VERSION 5.7 ;
BUSBITCHARS "[]" ;
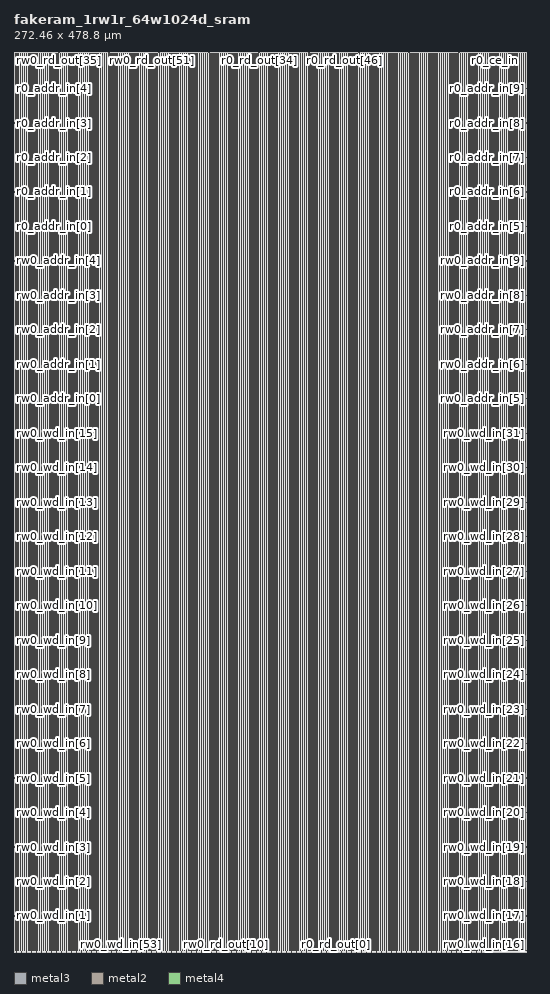
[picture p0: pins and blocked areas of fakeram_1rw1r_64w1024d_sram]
MACRO fakeram_1rw1r_64w1024d_sram
  FOREIGN fakeram_1rw1r_64w1024d_sram 0 0 ;
  SYMMETRY X Y R90 ;
  SIZE 272.460 BY 478.800 ;
  CLASS BLOCK ;
  PIN rw0_wd_in[0]
    DIRECTION INPUT ;
    USE SIGNAL ;
    SHAPE ABUTMENT ;
    PORT
      LAYER metal3 ;
      RECT 0.000 0.805 0.210 0.875 ;
    END
  END rw0_wd_in[0]
  PIN rw0_wd_in[1]
    DIRECTION INPUT ;
    USE SIGNAL ;
    SHAPE ABUTMENT ;
    PORT
      LAYER metal3 ;
      RECT 0.000 19.145 0.210 19.215 ;
    END
  END rw0_wd_in[1]
  PIN rw0_wd_in[2]
    DIRECTION INPUT ;
    USE SIGNAL ;
    SHAPE ABUTMENT ;
    PORT
      LAYER metal3 ;
      RECT 0.000 37.485 0.210 37.555 ;
    END
  END rw0_wd_in[2]
  PIN rw0_wd_in[3]
    DIRECTION INPUT ;
    USE SIGNAL ;
    SHAPE ABUTMENT ;
    PORT
      LAYER metal3 ;
      RECT 0.000 55.825 0.210 55.895 ;
    END
  END rw0_wd_in[3]
  PIN rw0_wd_in[4]
    DIRECTION INPUT ;
    USE SIGNAL ;
    SHAPE ABUTMENT ;
    PORT
      LAYER metal3 ;
      RECT 0.000 74.165 0.210 74.235 ;
    END
  END rw0_wd_in[4]
  PIN rw0_wd_in[5]
    DIRECTION INPUT ;
    USE SIGNAL ;
    SHAPE ABUTMENT ;
    PORT
      LAYER metal3 ;
      RECT 0.000 92.505 0.210 92.575 ;
    END
  END rw0_wd_in[5]
  PIN rw0_wd_in[6]
    DIRECTION INPUT ;
    USE SIGNAL ;
    SHAPE ABUTMENT ;
    PORT
      LAYER metal3 ;
      RECT 0.000 110.845 0.210 110.915 ;
    END
  END rw0_wd_in[6]
  PIN rw0_wd_in[7]
    DIRECTION INPUT ;
    USE SIGNAL ;
    SHAPE ABUTMENT ;
    PORT
      LAYER metal3 ;
      RECT 0.000 129.185 0.210 129.255 ;
    END
  END rw0_wd_in[7]
  PIN rw0_wd_in[8]
    DIRECTION INPUT ;
    USE SIGNAL ;
    SHAPE ABUTMENT ;
    PORT
      LAYER metal3 ;
      RECT 0.000 147.525 0.210 147.595 ;
    END
  END rw0_wd_in[8]
  PIN rw0_wd_in[9]
    DIRECTION INPUT ;
    USE SIGNAL ;
    SHAPE ABUTMENT ;
    PORT
      LAYER metal3 ;
      RECT 0.000 165.865 0.210 165.935 ;
    END
  END rw0_wd_in[9]
  PIN rw0_wd_in[10]
    DIRECTION INPUT ;
    USE SIGNAL ;
    SHAPE ABUTMENT ;
    PORT
      LAYER metal3 ;
      RECT 0.000 184.205 0.210 184.275 ;
    END
  END rw0_wd_in[10]
  PIN rw0_wd_in[11]
    DIRECTION INPUT ;
    USE SIGNAL ;
    SHAPE ABUTMENT ;
    PORT
      LAYER metal3 ;
      RECT 0.000 202.545 0.210 202.615 ;
    END
  END rw0_wd_in[11]
  PIN rw0_wd_in[12]
    DIRECTION INPUT ;
    USE SIGNAL ;
    SHAPE ABUTMENT ;
    PORT
      LAYER metal3 ;
      RECT 0.000 220.885 0.210 220.955 ;
    END
  END rw0_wd_in[12]
  PIN rw0_wd_in[13]
    DIRECTION INPUT ;
    USE SIGNAL ;
    SHAPE ABUTMENT ;
    PORT
      LAYER metal3 ;
      RECT 0.000 239.225 0.210 239.295 ;
    END
  END rw0_wd_in[13]
  PIN rw0_wd_in[14]
    DIRECTION INPUT ;
    USE SIGNAL ;
    SHAPE ABUTMENT ;
    PORT
      LAYER metal3 ;
      RECT 0.000 257.565 0.210 257.635 ;
    END
  END rw0_wd_in[14]
  PIN rw0_wd_in[15]
    DIRECTION INPUT ;
    USE SIGNAL ;
    SHAPE ABUTMENT ;
    PORT
      LAYER metal3 ;
      RECT 0.000 275.905 0.210 275.975 ;
    END
  END rw0_wd_in[15]
  PIN rw0_wd_in[16]
    DIRECTION INPUT ;
    USE SIGNAL ;
    SHAPE ABUTMENT ;
    PORT
      LAYER metal3 ;
      RECT 272.250 0.805 272.460 0.875 ;
    END
  END rw0_wd_in[16]
  PIN rw0_wd_in[17]
    DIRECTION INPUT ;
    USE SIGNAL ;
    SHAPE ABUTMENT ;
    PORT
      LAYER metal3 ;
      RECT 272.250 19.145 272.460 19.215 ;
    END
  END rw0_wd_in[17]
  PIN rw0_wd_in[18]
    DIRECTION INPUT ;
    USE SIGNAL ;
    SHAPE ABUTMENT ;
    PORT
      LAYER metal3 ;
      RECT 272.250 37.485 272.460 37.555 ;
    END
  END rw0_wd_in[18]
  PIN rw0_wd_in[19]
    DIRECTION INPUT ;
    USE SIGNAL ;
    SHAPE ABUTMENT ;
    PORT
      LAYER metal3 ;
      RECT 272.250 55.825 272.460 55.895 ;
    END
  END rw0_wd_in[19]
  PIN rw0_wd_in[20]
    DIRECTION INPUT ;
    USE SIGNAL ;
    SHAPE ABUTMENT ;
    PORT
      LAYER metal3 ;
      RECT 272.250 74.165 272.460 74.235 ;
    END
  END rw0_wd_in[20]
  PIN rw0_wd_in[21]
    DIRECTION INPUT ;
    USE SIGNAL ;
    SHAPE ABUTMENT ;
    PORT
      LAYER metal3 ;
      RECT 272.250 92.505 272.460 92.575 ;
    END
  END rw0_wd_in[21]
  PIN rw0_wd_in[22]
    DIRECTION INPUT ;
    USE SIGNAL ;
    SHAPE ABUTMENT ;
    PORT
      LAYER metal3 ;
      RECT 272.250 110.845 272.460 110.915 ;
    END
  END rw0_wd_in[22]
  PIN rw0_wd_in[23]
    DIRECTION INPUT ;
    USE SIGNAL ;
    SHAPE ABUTMENT ;
    PORT
      LAYER metal3 ;
      RECT 272.250 129.185 272.460 129.255 ;
    END
  END rw0_wd_in[23]
  PIN rw0_wd_in[24]
    DIRECTION INPUT ;
    USE SIGNAL ;
    SHAPE ABUTMENT ;
    PORT
      LAYER metal3 ;
      RECT 272.250 147.525 272.460 147.595 ;
    END
  END rw0_wd_in[24]
  PIN rw0_wd_in[25]
    DIRECTION INPUT ;
    USE SIGNAL ;
    SHAPE ABUTMENT ;
    PORT
      LAYER metal3 ;
      RECT 272.250 165.865 272.460 165.935 ;
    END
  END rw0_wd_in[25]
  PIN rw0_wd_in[26]
    DIRECTION INPUT ;
    USE SIGNAL ;
    SHAPE ABUTMENT ;
    PORT
      LAYER metal3 ;
      RECT 272.250 184.205 272.460 184.275 ;
    END
  END rw0_wd_in[26]
  PIN rw0_wd_in[27]
    DIRECTION INPUT ;
    USE SIGNAL ;
    SHAPE ABUTMENT ;
    PORT
      LAYER metal3 ;
      RECT 272.250 202.545 272.460 202.615 ;
    END
  END rw0_wd_in[27]
  PIN rw0_wd_in[28]
    DIRECTION INPUT ;
    USE SIGNAL ;
    SHAPE ABUTMENT ;
    PORT
      LAYER metal3 ;
      RECT 272.250 220.885 272.460 220.955 ;
    END
  END rw0_wd_in[28]
  PIN rw0_wd_in[29]
    DIRECTION INPUT ;
    USE SIGNAL ;
    SHAPE ABUTMENT ;
    PORT
      LAYER metal3 ;
      RECT 272.250 239.225 272.460 239.295 ;
    END
  END rw0_wd_in[29]
  PIN rw0_wd_in[30]
    DIRECTION INPUT ;
    USE SIGNAL ;
    SHAPE ABUTMENT ;
    PORT
      LAYER metal3 ;
      RECT 272.250 257.565 272.460 257.635 ;
    END
  END rw0_wd_in[30]
  PIN rw0_wd_in[31]
    DIRECTION INPUT ;
    USE SIGNAL ;
    SHAPE ABUTMENT ;
    PORT
      LAYER metal3 ;
      RECT 272.250 275.905 272.460 275.975 ;
    END
  END rw0_wd_in[31]
  PIN rw0_wd_in[32]
    DIRECTION INPUT ;
    USE SIGNAL ;
    SHAPE ABUTMENT ;
    PORT
      LAYER metal2 ;
      RECT 1.105 0.000 1.175 0.210 ;
    END
  END rw0_wd_in[32]
  PIN rw0_wd_in[33]
    DIRECTION INPUT ;
    USE SIGNAL ;
    SHAPE ABUTMENT ;
    PORT
      LAYER metal2 ;
      RECT 3.765 0.000 3.835 0.210 ;
    END
  END rw0_wd_in[33]
  PIN rw0_wd_in[34]
    DIRECTION INPUT ;
    USE SIGNAL ;
    SHAPE ABUTMENT ;
    PORT
      LAYER metal2 ;
      RECT 6.425 0.000 6.495 0.210 ;
    END
  END rw0_wd_in[34]
  PIN rw0_wd_in[35]
    DIRECTION INPUT ;
    USE SIGNAL ;
    SHAPE ABUTMENT ;
    PORT
      LAYER metal2 ;
      RECT 9.085 0.000 9.155 0.210 ;
    END
  END rw0_wd_in[35]
  PIN rw0_wd_in[36]
    DIRECTION INPUT ;
    USE SIGNAL ;
    SHAPE ABUTMENT ;
    PORT
      LAYER metal2 ;
      RECT 11.745 0.000 11.815 0.210 ;
    END
  END rw0_wd_in[36]
  PIN rw0_wd_in[37]
    DIRECTION INPUT ;
    USE SIGNAL ;
    SHAPE ABUTMENT ;
    PORT
      LAYER metal2 ;
      RECT 14.405 0.000 14.475 0.210 ;
    END
  END rw0_wd_in[37]
  PIN rw0_wd_in[38]
    DIRECTION INPUT ;
    USE SIGNAL ;
    SHAPE ABUTMENT ;
    PORT
      LAYER metal2 ;
      RECT 17.065 0.000 17.135 0.210 ;
    END
  END rw0_wd_in[38]
  PIN rw0_wd_in[39]
    DIRECTION INPUT ;
    USE SIGNAL ;
    SHAPE ABUTMENT ;
    PORT
      LAYER metal2 ;
      RECT 19.725 0.000 19.795 0.210 ;
    END
  END rw0_wd_in[39]
  PIN rw0_wd_in[40]
    DIRECTION INPUT ;
    USE SIGNAL ;
    SHAPE ABUTMENT ;
    PORT
      LAYER metal2 ;
      RECT 22.385 0.000 22.455 0.210 ;
    END
  END rw0_wd_in[40]
  PIN rw0_wd_in[41]
    DIRECTION INPUT ;
    USE SIGNAL ;
    SHAPE ABUTMENT ;
    PORT
      LAYER metal2 ;
      RECT 25.045 0.000 25.115 0.210 ;
    END
  END rw0_wd_in[41]
  PIN rw0_wd_in[42]
    DIRECTION INPUT ;
    USE SIGNAL ;
    SHAPE ABUTMENT ;
    PORT
      LAYER metal2 ;
      RECT 27.705 0.000 27.775 0.210 ;
    END
  END rw0_wd_in[42]
  PIN rw0_wd_in[43]
    DIRECTION INPUT ;
    USE SIGNAL ;
    SHAPE ABUTMENT ;
    PORT
      LAYER metal2 ;
      RECT 30.365 0.000 30.435 0.210 ;
    END
  END rw0_wd_in[43]
  PIN rw0_wd_in[44]
    DIRECTION INPUT ;
    USE SIGNAL ;
    SHAPE ABUTMENT ;
    PORT
      LAYER metal2 ;
      RECT 33.025 0.000 33.095 0.210 ;
    END
  END rw0_wd_in[44]
  PIN rw0_wd_in[45]
    DIRECTION INPUT ;
    USE SIGNAL ;
    SHAPE ABUTMENT ;
    PORT
      LAYER metal2 ;
      RECT 35.685 0.000 35.755 0.210 ;
    END
  END rw0_wd_in[45]
  PIN rw0_wd_in[46]
    DIRECTION INPUT ;
    USE SIGNAL ;
    SHAPE ABUTMENT ;
    PORT
      LAYER metal2 ;
      RECT 38.345 0.000 38.415 0.210 ;
    END
  END rw0_wd_in[46]
  PIN rw0_wd_in[47]
    DIRECTION INPUT ;
    USE SIGNAL ;
    SHAPE ABUTMENT ;
    PORT
      LAYER metal2 ;
      RECT 41.005 0.000 41.075 0.210 ;
    END
  END rw0_wd_in[47]
  PIN rw0_wd_in[48]
    DIRECTION INPUT ;
    USE SIGNAL ;
    SHAPE ABUTMENT ;
    PORT
      LAYER metal2 ;
      RECT 43.665 0.000 43.735 0.210 ;
    END
  END rw0_wd_in[48]
  PIN rw0_wd_in[49]
    DIRECTION INPUT ;
    USE SIGNAL ;
    SHAPE ABUTMENT ;
    PORT
      LAYER metal2 ;
      RECT 46.325 0.000 46.395 0.210 ;
    END
  END rw0_wd_in[49]
  PIN rw0_wd_in[50]
    DIRECTION INPUT ;
    USE SIGNAL ;
    SHAPE ABUTMENT ;
    PORT
      LAYER metal2 ;
      RECT 48.985 0.000 49.055 0.210 ;
    END
  END rw0_wd_in[50]
  PIN rw0_wd_in[51]
    DIRECTION INPUT ;
    USE SIGNAL ;
    SHAPE ABUTMENT ;
    PORT
      LAYER metal2 ;
      RECT 51.645 0.000 51.715 0.210 ;
    END
  END rw0_wd_in[51]
  PIN rw0_wd_in[52]
    DIRECTION INPUT ;
    USE SIGNAL ;
    SHAPE ABUTMENT ;
    PORT
      LAYER metal2 ;
      RECT 54.305 0.000 54.375 0.210 ;
    END
  END rw0_wd_in[52]
  PIN rw0_wd_in[53]
    DIRECTION INPUT ;
    USE SIGNAL ;
    SHAPE ABUTMENT ;
    PORT
      LAYER metal2 ;
      RECT 56.965 0.000 57.035 0.210 ;
    END
  END rw0_wd_in[53]
  PIN rw0_wd_in[54]
    DIRECTION INPUT ;
    USE SIGNAL ;
    SHAPE ABUTMENT ;
    PORT
      LAYER metal2 ;
      RECT 59.625 0.000 59.695 0.210 ;
    END
  END rw0_wd_in[54]
  PIN rw0_wd_in[55]
    DIRECTION INPUT ;
    USE SIGNAL ;
    SHAPE ABUTMENT ;
    PORT
      LAYER metal2 ;
      RECT 62.285 0.000 62.355 0.210 ;
    END
  END rw0_wd_in[55]
  PIN rw0_wd_in[56]
    DIRECTION INPUT ;
    USE SIGNAL ;
    SHAPE ABUTMENT ;
    PORT
      LAYER metal2 ;
      RECT 64.945 0.000 65.015 0.210 ;
    END
  END rw0_wd_in[56]
  PIN rw0_wd_in[57]
    DIRECTION INPUT ;
    USE SIGNAL ;
    SHAPE ABUTMENT ;
    PORT
      LAYER metal2 ;
      RECT 67.605 0.000 67.675 0.210 ;
    END
  END rw0_wd_in[57]
  PIN rw0_wd_in[58]
    DIRECTION INPUT ;
    USE SIGNAL ;
    SHAPE ABUTMENT ;
    PORT
      LAYER metal2 ;
      RECT 70.265 0.000 70.335 0.210 ;
    END
  END rw0_wd_in[58]
  PIN rw0_wd_in[59]
    DIRECTION INPUT ;
    USE SIGNAL ;
    SHAPE ABUTMENT ;
    PORT
      LAYER metal2 ;
      RECT 72.925 0.000 72.995 0.210 ;
    END
  END rw0_wd_in[59]
  PIN rw0_wd_in[60]
    DIRECTION INPUT ;
    USE SIGNAL ;
    SHAPE ABUTMENT ;
    PORT
      LAYER metal2 ;
      RECT 75.585 0.000 75.655 0.210 ;
    END
  END rw0_wd_in[60]
  PIN rw0_wd_in[61]
    DIRECTION INPUT ;
    USE SIGNAL ;
    SHAPE ABUTMENT ;
    PORT
      LAYER metal2 ;
      RECT 78.245 0.000 78.315 0.210 ;
    END
  END rw0_wd_in[61]
  PIN rw0_wd_in[62]
    DIRECTION INPUT ;
    USE SIGNAL ;
    SHAPE ABUTMENT ;
    PORT
      LAYER metal2 ;
      RECT 80.905 0.000 80.975 0.210 ;
    END
  END rw0_wd_in[62]
  PIN rw0_wd_in[63]
    DIRECTION INPUT ;
    USE SIGNAL ;
    SHAPE ABUTMENT ;
    PORT
      LAYER metal2 ;
      RECT 83.565 0.000 83.635 0.210 ;
    END
  END rw0_wd_in[63]
  PIN rw0_rd_out[0]
    DIRECTION OUTPUT ;
    USE SIGNAL ;
    SHAPE ABUTMENT ;
    PORT
      LAYER metal2 ;
      RECT 86.225 0.000 86.295 0.210 ;
    END
  END rw0_rd_out[0]
  PIN rw0_rd_out[1]
    DIRECTION OUTPUT ;
    USE SIGNAL ;
    SHAPE ABUTMENT ;
    PORT
      LAYER metal2 ;
      RECT 88.885 0.000 88.955 0.210 ;
    END
  END rw0_rd_out[1]
  PIN rw0_rd_out[2]
    DIRECTION OUTPUT ;
    USE SIGNAL ;
    SHAPE ABUTMENT ;
    PORT
      LAYER metal2 ;
      RECT 91.545 0.000 91.615 0.210 ;
    END
  END rw0_rd_out[2]
  PIN rw0_rd_out[3]
    DIRECTION OUTPUT ;
    USE SIGNAL ;
    SHAPE ABUTMENT ;
    PORT
      LAYER metal2 ;
      RECT 94.205 0.000 94.275 0.210 ;
    END
  END rw0_rd_out[3]
  PIN rw0_rd_out[4]
    DIRECTION OUTPUT ;
    USE SIGNAL ;
    SHAPE ABUTMENT ;
    PORT
      LAYER metal2 ;
      RECT 96.865 0.000 96.935 0.210 ;
    END
  END rw0_rd_out[4]
  PIN rw0_rd_out[5]
    DIRECTION OUTPUT ;
    USE SIGNAL ;
    SHAPE ABUTMENT ;
    PORT
      LAYER metal2 ;
      RECT 99.525 0.000 99.595 0.210 ;
    END
  END rw0_rd_out[5]
  PIN rw0_rd_out[6]
    DIRECTION OUTPUT ;
    USE SIGNAL ;
    SHAPE ABUTMENT ;
    PORT
      LAYER metal2 ;
      RECT 102.185 0.000 102.255 0.210 ;
    END
  END rw0_rd_out[6]
  PIN rw0_rd_out[7]
    DIRECTION OUTPUT ;
    USE SIGNAL ;
    SHAPE ABUTMENT ;
    PORT
      LAYER metal2 ;
      RECT 104.845 0.000 104.915 0.210 ;
    END
  END rw0_rd_out[7]
  PIN rw0_rd_out[8]
    DIRECTION OUTPUT ;
    USE SIGNAL ;
    SHAPE ABUTMENT ;
    PORT
      LAYER metal2 ;
      RECT 107.505 0.000 107.575 0.210 ;
    END
  END rw0_rd_out[8]
  PIN rw0_rd_out[9]
    DIRECTION OUTPUT ;
    USE SIGNAL ;
    SHAPE ABUTMENT ;
    PORT
      LAYER metal2 ;
      RECT 110.165 0.000 110.235 0.210 ;
    END
  END rw0_rd_out[9]
  PIN rw0_rd_out[10]
    DIRECTION OUTPUT ;
    USE SIGNAL ;
    SHAPE ABUTMENT ;
    PORT
      LAYER metal2 ;
      RECT 112.825 0.000 112.895 0.210 ;
    END
  END rw0_rd_out[10]
  PIN rw0_rd_out[11]
    DIRECTION OUTPUT ;
    USE SIGNAL ;
    SHAPE ABUTMENT ;
    PORT
      LAYER metal2 ;
      RECT 115.485 0.000 115.555 0.210 ;
    END
  END rw0_rd_out[11]
  PIN rw0_rd_out[12]
    DIRECTION OUTPUT ;
    USE SIGNAL ;
    SHAPE ABUTMENT ;
    PORT
      LAYER metal2 ;
      RECT 118.145 0.000 118.215 0.210 ;
    END
  END rw0_rd_out[12]
  PIN rw0_rd_out[13]
    DIRECTION OUTPUT ;
    USE SIGNAL ;
    SHAPE ABUTMENT ;
    PORT
      LAYER metal2 ;
      RECT 120.805 0.000 120.875 0.210 ;
    END
  END rw0_rd_out[13]
  PIN rw0_rd_out[14]
    DIRECTION OUTPUT ;
    USE SIGNAL ;
    SHAPE ABUTMENT ;
    PORT
      LAYER metal2 ;
      RECT 123.465 0.000 123.535 0.210 ;
    END
  END rw0_rd_out[14]
  PIN rw0_rd_out[15]
    DIRECTION OUTPUT ;
    USE SIGNAL ;
    SHAPE ABUTMENT ;
    PORT
      LAYER metal2 ;
      RECT 126.125 0.000 126.195 0.210 ;
    END
  END rw0_rd_out[15]
  PIN rw0_rd_out[16]
    DIRECTION OUTPUT ;
    USE SIGNAL ;
    SHAPE ABUTMENT ;
    PORT
      LAYER metal2 ;
      RECT 128.785 0.000 128.855 0.210 ;
    END
  END rw0_rd_out[16]
  PIN rw0_rd_out[17]
    DIRECTION OUTPUT ;
    USE SIGNAL ;
    SHAPE ABUTMENT ;
    PORT
      LAYER metal2 ;
      RECT 131.445 0.000 131.515 0.210 ;
    END
  END rw0_rd_out[17]
  PIN rw0_rd_out[18]
    DIRECTION OUTPUT ;
    USE SIGNAL ;
    SHAPE ABUTMENT ;
    PORT
      LAYER metal2 ;
      RECT 134.105 0.000 134.175 0.210 ;
    END
  END rw0_rd_out[18]
  PIN rw0_rd_out[19]
    DIRECTION OUTPUT ;
    USE SIGNAL ;
    SHAPE ABUTMENT ;
    PORT
      LAYER metal2 ;
      RECT 136.765 0.000 136.835 0.210 ;
    END
  END rw0_rd_out[19]
  PIN rw0_rd_out[20]
    DIRECTION OUTPUT ;
    USE SIGNAL ;
    SHAPE ABUTMENT ;
    PORT
      LAYER metal2 ;
      RECT 139.425 0.000 139.495 0.210 ;
    END
  END rw0_rd_out[20]
  PIN rw0_rd_out[21]
    DIRECTION OUTPUT ;
    USE SIGNAL ;
    SHAPE ABUTMENT ;
    PORT
      LAYER metal2 ;
      RECT 142.085 0.000 142.155 0.210 ;
    END
  END rw0_rd_out[21]
  PIN rw0_rd_out[22]
    DIRECTION OUTPUT ;
    USE SIGNAL ;
    SHAPE ABUTMENT ;
    PORT
      LAYER metal2 ;
      RECT 144.745 0.000 144.815 0.210 ;
    END
  END rw0_rd_out[22]
  PIN rw0_rd_out[23]
    DIRECTION OUTPUT ;
    USE SIGNAL ;
    SHAPE ABUTMENT ;
    PORT
      LAYER metal2 ;
      RECT 147.405 0.000 147.475 0.210 ;
    END
  END rw0_rd_out[23]
  PIN rw0_rd_out[24]
    DIRECTION OUTPUT ;
    USE SIGNAL ;
    SHAPE ABUTMENT ;
    PORT
      LAYER metal2 ;
      RECT 150.065 0.000 150.135 0.210 ;
    END
  END rw0_rd_out[24]
  PIN rw0_rd_out[25]
    DIRECTION OUTPUT ;
    USE SIGNAL ;
    SHAPE ABUTMENT ;
    PORT
      LAYER metal2 ;
      RECT 152.725 0.000 152.795 0.210 ;
    END
  END rw0_rd_out[25]
  PIN rw0_rd_out[26]
    DIRECTION OUTPUT ;
    USE SIGNAL ;
    SHAPE ABUTMENT ;
    PORT
      LAYER metal2 ;
      RECT 155.385 0.000 155.455 0.210 ;
    END
  END rw0_rd_out[26]
  PIN rw0_rd_out[27]
    DIRECTION OUTPUT ;
    USE SIGNAL ;
    SHAPE ABUTMENT ;
    PORT
      LAYER metal2 ;
      RECT 158.045 0.000 158.115 0.210 ;
    END
  END rw0_rd_out[27]
  PIN rw0_rd_out[28]
    DIRECTION OUTPUT ;
    USE SIGNAL ;
    SHAPE ABUTMENT ;
    PORT
      LAYER metal2 ;
      RECT 160.705 0.000 160.775 0.210 ;
    END
  END rw0_rd_out[28]
  PIN rw0_rd_out[29]
    DIRECTION OUTPUT ;
    USE SIGNAL ;
    SHAPE ABUTMENT ;
    PORT
      LAYER metal2 ;
      RECT 163.365 0.000 163.435 0.210 ;
    END
  END rw0_rd_out[29]
  PIN rw0_rd_out[30]
    DIRECTION OUTPUT ;
    USE SIGNAL ;
    SHAPE ABUTMENT ;
    PORT
      LAYER metal2 ;
      RECT 166.025 0.000 166.095 0.210 ;
    END
  END rw0_rd_out[30]
  PIN rw0_rd_out[31]
    DIRECTION OUTPUT ;
    USE SIGNAL ;
    SHAPE ABUTMENT ;
    PORT
      LAYER metal2 ;
      RECT 168.685 0.000 168.755 0.210 ;
    END
  END rw0_rd_out[31]
  PIN rw0_rd_out[32]
    DIRECTION OUTPUT ;
    USE SIGNAL ;
    SHAPE ABUTMENT ;
    PORT
      LAYER metal2 ;
      RECT 1.105 478.590 1.175 478.800 ;
    END
  END rw0_rd_out[32]
  PIN rw0_rd_out[33]
    DIRECTION OUTPUT ;
    USE SIGNAL ;
    SHAPE ABUTMENT ;
    PORT
      LAYER metal2 ;
      RECT 4.905 478.590 4.975 478.800 ;
    END
  END rw0_rd_out[33]
  PIN rw0_rd_out[34]
    DIRECTION OUTPUT ;
    USE SIGNAL ;
    SHAPE ABUTMENT ;
    PORT
      LAYER metal2 ;
      RECT 8.705 478.590 8.775 478.800 ;
    END
  END rw0_rd_out[34]
  PIN rw0_rd_out[35]
    DIRECTION OUTPUT ;
    USE SIGNAL ;
    SHAPE ABUTMENT ;
    PORT
      LAYER metal2 ;
      RECT 12.505 478.590 12.575 478.800 ;
    END
  END rw0_rd_out[35]
  PIN rw0_rd_out[36]
    DIRECTION OUTPUT ;
    USE SIGNAL ;
    SHAPE ABUTMENT ;
    PORT
      LAYER metal2 ;
      RECT 16.305 478.590 16.375 478.800 ;
    END
  END rw0_rd_out[36]
  PIN rw0_rd_out[37]
    DIRECTION OUTPUT ;
    USE SIGNAL ;
    SHAPE ABUTMENT ;
    PORT
      LAYER metal2 ;
      RECT 20.105 478.590 20.175 478.800 ;
    END
  END rw0_rd_out[37]
  PIN rw0_rd_out[38]
    DIRECTION OUTPUT ;
    USE SIGNAL ;
    SHAPE ABUTMENT ;
    PORT
      LAYER metal2 ;
      RECT 23.905 478.590 23.975 478.800 ;
    END
  END rw0_rd_out[38]
  PIN rw0_rd_out[39]
    DIRECTION OUTPUT ;
    USE SIGNAL ;
    SHAPE ABUTMENT ;
    PORT
      LAYER metal2 ;
      RECT 27.705 478.590 27.775 478.800 ;
    END
  END rw0_rd_out[39]
  PIN rw0_rd_out[40]
    DIRECTION OUTPUT ;
    USE SIGNAL ;
    SHAPE ABUTMENT ;
    PORT
      LAYER metal2 ;
      RECT 31.505 478.590 31.575 478.800 ;
    END
  END rw0_rd_out[40]
  PIN rw0_rd_out[41]
    DIRECTION OUTPUT ;
    USE SIGNAL ;
    SHAPE ABUTMENT ;
    PORT
      LAYER metal2 ;
      RECT 35.305 478.590 35.375 478.800 ;
    END
  END rw0_rd_out[41]
  PIN rw0_rd_out[42]
    DIRECTION OUTPUT ;
    USE SIGNAL ;
    SHAPE ABUTMENT ;
    PORT
      LAYER metal2 ;
      RECT 39.105 478.590 39.175 478.800 ;
    END
  END rw0_rd_out[42]
  PIN rw0_rd_out[43]
    DIRECTION OUTPUT ;
    USE SIGNAL ;
    SHAPE ABUTMENT ;
    PORT
      LAYER metal2 ;
      RECT 42.905 478.590 42.975 478.800 ;
    END
  END rw0_rd_out[43]
  PIN rw0_rd_out[44]
    DIRECTION OUTPUT ;
    USE SIGNAL ;
    SHAPE ABUTMENT ;
    PORT
      LAYER metal2 ;
      RECT 46.705 478.590 46.775 478.800 ;
    END
  END rw0_rd_out[44]
  PIN rw0_rd_out[45]
    DIRECTION OUTPUT ;
    USE SIGNAL ;
    SHAPE ABUTMENT ;
    PORT
      LAYER metal2 ;
      RECT 50.505 478.590 50.575 478.800 ;
    END
  END rw0_rd_out[45]
  PIN rw0_rd_out[46]
    DIRECTION OUTPUT ;
    USE SIGNAL ;
    SHAPE ABUTMENT ;
    PORT
      LAYER metal2 ;
      RECT 54.305 478.590 54.375 478.800 ;
    END
  END rw0_rd_out[46]
  PIN rw0_rd_out[47]
    DIRECTION OUTPUT ;
    USE SIGNAL ;
    SHAPE ABUTMENT ;
    PORT
      LAYER metal2 ;
      RECT 58.105 478.590 58.175 478.800 ;
    END
  END rw0_rd_out[47]
  PIN rw0_rd_out[48]
    DIRECTION OUTPUT ;
    USE SIGNAL ;
    SHAPE ABUTMENT ;
    PORT
      LAYER metal2 ;
      RECT 61.905 478.590 61.975 478.800 ;
    END
  END rw0_rd_out[48]
  PIN rw0_rd_out[49]
    DIRECTION OUTPUT ;
    USE SIGNAL ;
    SHAPE ABUTMENT ;
    PORT
      LAYER metal2 ;
      RECT 65.705 478.590 65.775 478.800 ;
    END
  END rw0_rd_out[49]
  PIN rw0_rd_out[50]
    DIRECTION OUTPUT ;
    USE SIGNAL ;
    SHAPE ABUTMENT ;
    PORT
      LAYER metal2 ;
      RECT 69.505 478.590 69.575 478.800 ;
    END
  END rw0_rd_out[50]
  PIN rw0_rd_out[51]
    DIRECTION OUTPUT ;
    USE SIGNAL ;
    SHAPE ABUTMENT ;
    PORT
      LAYER metal2 ;
      RECT 73.305 478.590 73.375 478.800 ;
    END
  END rw0_rd_out[51]
  PIN rw0_rd_out[52]
    DIRECTION OUTPUT ;
    USE SIGNAL ;
    SHAPE ABUTMENT ;
    PORT
      LAYER metal2 ;
      RECT 77.105 478.590 77.175 478.800 ;
    END
  END rw0_rd_out[52]
  PIN rw0_rd_out[53]
    DIRECTION OUTPUT ;
    USE SIGNAL ;
    SHAPE ABUTMENT ;
    PORT
      LAYER metal2 ;
      RECT 80.905 478.590 80.975 478.800 ;
    END
  END rw0_rd_out[53]
  PIN rw0_rd_out[54]
    DIRECTION OUTPUT ;
    USE SIGNAL ;
    SHAPE ABUTMENT ;
    PORT
      LAYER metal2 ;
      RECT 84.705 478.590 84.775 478.800 ;
    END
  END rw0_rd_out[54]
  PIN rw0_rd_out[55]
    DIRECTION OUTPUT ;
    USE SIGNAL ;
    SHAPE ABUTMENT ;
    PORT
      LAYER metal2 ;
      RECT 88.505 478.590 88.575 478.800 ;
    END
  END rw0_rd_out[55]
  PIN rw0_rd_out[56]
    DIRECTION OUTPUT ;
    USE SIGNAL ;
    SHAPE ABUTMENT ;
    PORT
      LAYER metal2 ;
      RECT 92.305 478.590 92.375 478.800 ;
    END
  END rw0_rd_out[56]
  PIN rw0_rd_out[57]
    DIRECTION OUTPUT ;
    USE SIGNAL ;
    SHAPE ABUTMENT ;
    PORT
      LAYER metal2 ;
      RECT 96.105 478.590 96.175 478.800 ;
    END
  END rw0_rd_out[57]
  PIN rw0_rd_out[58]
    DIRECTION OUTPUT ;
    USE SIGNAL ;
    SHAPE ABUTMENT ;
    PORT
      LAYER metal2 ;
      RECT 99.905 478.590 99.975 478.800 ;
    END
  END rw0_rd_out[58]
  PIN rw0_rd_out[59]
    DIRECTION OUTPUT ;
    USE SIGNAL ;
    SHAPE ABUTMENT ;
    PORT
      LAYER metal2 ;
      RECT 103.705 478.590 103.775 478.800 ;
    END
  END rw0_rd_out[59]
  PIN rw0_rd_out[60]
    DIRECTION OUTPUT ;
    USE SIGNAL ;
    SHAPE ABUTMENT ;
    PORT
      LAYER metal2 ;
      RECT 107.505 478.590 107.575 478.800 ;
    END
  END rw0_rd_out[60]
  PIN rw0_rd_out[61]
    DIRECTION OUTPUT ;
    USE SIGNAL ;
    SHAPE ABUTMENT ;
    PORT
      LAYER metal2 ;
      RECT 111.305 478.590 111.375 478.800 ;
    END
  END rw0_rd_out[61]
  PIN rw0_rd_out[62]
    DIRECTION OUTPUT ;
    USE SIGNAL ;
    SHAPE ABUTMENT ;
    PORT
      LAYER metal2 ;
      RECT 115.105 478.590 115.175 478.800 ;
    END
  END rw0_rd_out[62]
  PIN rw0_rd_out[63]
    DIRECTION OUTPUT ;
    USE SIGNAL ;
    SHAPE ABUTMENT ;
    PORT
      LAYER metal2 ;
      RECT 118.905 478.590 118.975 478.800 ;
    END
  END rw0_rd_out[63]
  PIN r0_rd_out[0]
    DIRECTION OUTPUT ;
    USE SIGNAL ;
    SHAPE ABUTMENT ;
    PORT
      LAYER metal2 ;
      RECT 171.345 0.000 171.415 0.210 ;
    END
  END r0_rd_out[0]
  PIN r0_rd_out[1]
    DIRECTION OUTPUT ;
    USE SIGNAL ;
    SHAPE ABUTMENT ;
    PORT
      LAYER metal2 ;
      RECT 174.005 0.000 174.075 0.210 ;
    END
  END r0_rd_out[1]
  PIN r0_rd_out[2]
    DIRECTION OUTPUT ;
    USE SIGNAL ;
    SHAPE ABUTMENT ;
    PORT
      LAYER metal2 ;
      RECT 176.665 0.000 176.735 0.210 ;
    END
  END r0_rd_out[2]
  PIN r0_rd_out[3]
    DIRECTION OUTPUT ;
    USE SIGNAL ;
    SHAPE ABUTMENT ;
    PORT
      LAYER metal2 ;
      RECT 179.325 0.000 179.395 0.210 ;
    END
  END r0_rd_out[3]
  PIN r0_rd_out[4]
    DIRECTION OUTPUT ;
    USE SIGNAL ;
    SHAPE ABUTMENT ;
    PORT
      LAYER metal2 ;
      RECT 181.985 0.000 182.055 0.210 ;
    END
  END r0_rd_out[4]
  PIN r0_rd_out[5]
    DIRECTION OUTPUT ;
    USE SIGNAL ;
    SHAPE ABUTMENT ;
    PORT
      LAYER metal2 ;
      RECT 184.645 0.000 184.715 0.210 ;
    END
  END r0_rd_out[5]
  PIN r0_rd_out[6]
    DIRECTION OUTPUT ;
    USE SIGNAL ;
    SHAPE ABUTMENT ;
    PORT
      LAYER metal2 ;
      RECT 187.305 0.000 187.375 0.210 ;
    END
  END r0_rd_out[6]
  PIN r0_rd_out[7]
    DIRECTION OUTPUT ;
    USE SIGNAL ;
    SHAPE ABUTMENT ;
    PORT
      LAYER metal2 ;
      RECT 189.965 0.000 190.035 0.210 ;
    END
  END r0_rd_out[7]
  PIN r0_rd_out[8]
    DIRECTION OUTPUT ;
    USE SIGNAL ;
    SHAPE ABUTMENT ;
    PORT
      LAYER metal2 ;
      RECT 192.625 0.000 192.695 0.210 ;
    END
  END r0_rd_out[8]
  PIN r0_rd_out[9]
    DIRECTION OUTPUT ;
    USE SIGNAL ;
    SHAPE ABUTMENT ;
    PORT
      LAYER metal2 ;
      RECT 195.285 0.000 195.355 0.210 ;
    END
  END r0_rd_out[9]
  PIN r0_rd_out[10]
    DIRECTION OUTPUT ;
    USE SIGNAL ;
    SHAPE ABUTMENT ;
    PORT
      LAYER metal2 ;
      RECT 197.945 0.000 198.015 0.210 ;
    END
  END r0_rd_out[10]
  PIN r0_rd_out[11]
    DIRECTION OUTPUT ;
    USE SIGNAL ;
    SHAPE ABUTMENT ;
    PORT
      LAYER metal2 ;
      RECT 200.605 0.000 200.675 0.210 ;
    END
  END r0_rd_out[11]
  PIN r0_rd_out[12]
    DIRECTION OUTPUT ;
    USE SIGNAL ;
    SHAPE ABUTMENT ;
    PORT
      LAYER metal2 ;
      RECT 203.265 0.000 203.335 0.210 ;
    END
  END r0_rd_out[12]
  PIN r0_rd_out[13]
    DIRECTION OUTPUT ;
    USE SIGNAL ;
    SHAPE ABUTMENT ;
    PORT
      LAYER metal2 ;
      RECT 205.925 0.000 205.995 0.210 ;
    END
  END r0_rd_out[13]
  PIN r0_rd_out[14]
    DIRECTION OUTPUT ;
    USE SIGNAL ;
    SHAPE ABUTMENT ;
    PORT
      LAYER metal2 ;
      RECT 208.585 0.000 208.655 0.210 ;
    END
  END r0_rd_out[14]
  PIN r0_rd_out[15]
    DIRECTION OUTPUT ;
    USE SIGNAL ;
    SHAPE ABUTMENT ;
    PORT
      LAYER metal2 ;
      RECT 211.245 0.000 211.315 0.210 ;
    END
  END r0_rd_out[15]
  PIN r0_rd_out[16]
    DIRECTION OUTPUT ;
    USE SIGNAL ;
    SHAPE ABUTMENT ;
    PORT
      LAYER metal2 ;
      RECT 213.905 0.000 213.975 0.210 ;
    END
  END r0_rd_out[16]
  PIN r0_rd_out[17]
    DIRECTION OUTPUT ;
    USE SIGNAL ;
    SHAPE ABUTMENT ;
    PORT
      LAYER metal2 ;
      RECT 216.565 0.000 216.635 0.210 ;
    END
  END r0_rd_out[17]
  PIN r0_rd_out[18]
    DIRECTION OUTPUT ;
    USE SIGNAL ;
    SHAPE ABUTMENT ;
    PORT
      LAYER metal2 ;
      RECT 219.225 0.000 219.295 0.210 ;
    END
  END r0_rd_out[18]
  PIN r0_rd_out[19]
    DIRECTION OUTPUT ;
    USE SIGNAL ;
    SHAPE ABUTMENT ;
    PORT
      LAYER metal2 ;
      RECT 221.885 0.000 221.955 0.210 ;
    END
  END r0_rd_out[19]
  PIN r0_rd_out[20]
    DIRECTION OUTPUT ;
    USE SIGNAL ;
    SHAPE ABUTMENT ;
    PORT
      LAYER metal2 ;
      RECT 224.545 0.000 224.615 0.210 ;
    END
  END r0_rd_out[20]
  PIN r0_rd_out[21]
    DIRECTION OUTPUT ;
    USE SIGNAL ;
    SHAPE ABUTMENT ;
    PORT
      LAYER metal2 ;
      RECT 227.205 0.000 227.275 0.210 ;
    END
  END r0_rd_out[21]
  PIN r0_rd_out[22]
    DIRECTION OUTPUT ;
    USE SIGNAL ;
    SHAPE ABUTMENT ;
    PORT
      LAYER metal2 ;
      RECT 229.865 0.000 229.935 0.210 ;
    END
  END r0_rd_out[22]
  PIN r0_rd_out[23]
    DIRECTION OUTPUT ;
    USE SIGNAL ;
    SHAPE ABUTMENT ;
    PORT
      LAYER metal2 ;
      RECT 232.525 0.000 232.595 0.210 ;
    END
  END r0_rd_out[23]
  PIN r0_rd_out[24]
    DIRECTION OUTPUT ;
    USE SIGNAL ;
    SHAPE ABUTMENT ;
    PORT
      LAYER metal2 ;
      RECT 235.185 0.000 235.255 0.210 ;
    END
  END r0_rd_out[24]
  PIN r0_rd_out[25]
    DIRECTION OUTPUT ;
    USE SIGNAL ;
    SHAPE ABUTMENT ;
    PORT
      LAYER metal2 ;
      RECT 237.845 0.000 237.915 0.210 ;
    END
  END r0_rd_out[25]
  PIN r0_rd_out[26]
    DIRECTION OUTPUT ;
    USE SIGNAL ;
    SHAPE ABUTMENT ;
    PORT
      LAYER metal2 ;
      RECT 240.505 0.000 240.575 0.210 ;
    END
  END r0_rd_out[26]
  PIN r0_rd_out[27]
    DIRECTION OUTPUT ;
    USE SIGNAL ;
    SHAPE ABUTMENT ;
    PORT
      LAYER metal2 ;
      RECT 243.165 0.000 243.235 0.210 ;
    END
  END r0_rd_out[27]
  PIN r0_rd_out[28]
    DIRECTION OUTPUT ;
    USE SIGNAL ;
    SHAPE ABUTMENT ;
    PORT
      LAYER metal2 ;
      RECT 245.825 0.000 245.895 0.210 ;
    END
  END r0_rd_out[28]
  PIN r0_rd_out[29]
    DIRECTION OUTPUT ;
    USE SIGNAL ;
    SHAPE ABUTMENT ;
    PORT
      LAYER metal2 ;
      RECT 248.485 0.000 248.555 0.210 ;
    END
  END r0_rd_out[29]
  PIN r0_rd_out[30]
    DIRECTION OUTPUT ;
    USE SIGNAL ;
    SHAPE ABUTMENT ;
    PORT
      LAYER metal2 ;
      RECT 251.145 0.000 251.215 0.210 ;
    END
  END r0_rd_out[30]
  PIN r0_rd_out[31]
    DIRECTION OUTPUT ;
    USE SIGNAL ;
    SHAPE ABUTMENT ;
    PORT
      LAYER metal2 ;
      RECT 253.805 0.000 253.875 0.210 ;
    END
  END r0_rd_out[31]
  PIN r0_rd_out[32]
    DIRECTION OUTPUT ;
    USE SIGNAL ;
    SHAPE ABUTMENT ;
    PORT
      LAYER metal2 ;
      RECT 122.705 478.590 122.775 478.800 ;
    END
  END r0_rd_out[32]
  PIN r0_rd_out[33]
    DIRECTION OUTPUT ;
    USE SIGNAL ;
    SHAPE ABUTMENT ;
    PORT
      LAYER metal2 ;
      RECT 126.505 478.590 126.575 478.800 ;
    END
  END r0_rd_out[33]
  PIN r0_rd_out[34]
    DIRECTION OUTPUT ;
    USE SIGNAL ;
    SHAPE ABUTMENT ;
    PORT
      LAYER metal2 ;
      RECT 130.305 478.590 130.375 478.800 ;
    END
  END r0_rd_out[34]
  PIN r0_rd_out[35]
    DIRECTION OUTPUT ;
    USE SIGNAL ;
    SHAPE ABUTMENT ;
    PORT
      LAYER metal2 ;
      RECT 134.105 478.590 134.175 478.800 ;
    END
  END r0_rd_out[35]
  PIN r0_rd_out[36]
    DIRECTION OUTPUT ;
    USE SIGNAL ;
    SHAPE ABUTMENT ;
    PORT
      LAYER metal2 ;
      RECT 137.905 478.590 137.975 478.800 ;
    END
  END r0_rd_out[36]
  PIN r0_rd_out[37]
    DIRECTION OUTPUT ;
    USE SIGNAL ;
    SHAPE ABUTMENT ;
    PORT
      LAYER metal2 ;
      RECT 141.705 478.590 141.775 478.800 ;
    END
  END r0_rd_out[37]
  PIN r0_rd_out[38]
    DIRECTION OUTPUT ;
    USE SIGNAL ;
    SHAPE ABUTMENT ;
    PORT
      LAYER metal2 ;
      RECT 145.505 478.590 145.575 478.800 ;
    END
  END r0_rd_out[38]
  PIN r0_rd_out[39]
    DIRECTION OUTPUT ;
    USE SIGNAL ;
    SHAPE ABUTMENT ;
    PORT
      LAYER metal2 ;
      RECT 149.305 478.590 149.375 478.800 ;
    END
  END r0_rd_out[39]
  PIN r0_rd_out[40]
    DIRECTION OUTPUT ;
    USE SIGNAL ;
    SHAPE ABUTMENT ;
    PORT
      LAYER metal2 ;
      RECT 153.105 478.590 153.175 478.800 ;
    END
  END r0_rd_out[40]
  PIN r0_rd_out[41]
    DIRECTION OUTPUT ;
    USE SIGNAL ;
    SHAPE ABUTMENT ;
    PORT
      LAYER metal2 ;
      RECT 156.905 478.590 156.975 478.800 ;
    END
  END r0_rd_out[41]
  PIN r0_rd_out[42]
    DIRECTION OUTPUT ;
    USE SIGNAL ;
    SHAPE ABUTMENT ;
    PORT
      LAYER metal2 ;
      RECT 160.705 478.590 160.775 478.800 ;
    END
  END r0_rd_out[42]
  PIN r0_rd_out[43]
    DIRECTION OUTPUT ;
    USE SIGNAL ;
    SHAPE ABUTMENT ;
    PORT
      LAYER metal2 ;
      RECT 164.505 478.590 164.575 478.800 ;
    END
  END r0_rd_out[43]
  PIN r0_rd_out[44]
    DIRECTION OUTPUT ;
    USE SIGNAL ;
    SHAPE ABUTMENT ;
    PORT
      LAYER metal2 ;
      RECT 168.305 478.590 168.375 478.800 ;
    END
  END r0_rd_out[44]
  PIN r0_rd_out[45]
    DIRECTION OUTPUT ;
    USE SIGNAL ;
    SHAPE ABUTMENT ;
    PORT
      LAYER metal2 ;
      RECT 172.105 478.590 172.175 478.800 ;
    END
  END r0_rd_out[45]
  PIN r0_rd_out[46]
    DIRECTION OUTPUT ;
    USE SIGNAL ;
    SHAPE ABUTMENT ;
    PORT
      LAYER metal2 ;
      RECT 175.905 478.590 175.975 478.800 ;
    END
  END r0_rd_out[46]
  PIN r0_rd_out[47]
    DIRECTION OUTPUT ;
    USE SIGNAL ;
    SHAPE ABUTMENT ;
    PORT
      LAYER metal2 ;
      RECT 179.705 478.590 179.775 478.800 ;
    END
  END r0_rd_out[47]
  PIN r0_rd_out[48]
    DIRECTION OUTPUT ;
    USE SIGNAL ;
    SHAPE ABUTMENT ;
    PORT
      LAYER metal2 ;
      RECT 183.505 478.590 183.575 478.800 ;
    END
  END r0_rd_out[48]
  PIN r0_rd_out[49]
    DIRECTION OUTPUT ;
    USE SIGNAL ;
    SHAPE ABUTMENT ;
    PORT
      LAYER metal2 ;
      RECT 187.305 478.590 187.375 478.800 ;
    END
  END r0_rd_out[49]
  PIN r0_rd_out[50]
    DIRECTION OUTPUT ;
    USE SIGNAL ;
    SHAPE ABUTMENT ;
    PORT
      LAYER metal2 ;
      RECT 191.105 478.590 191.175 478.800 ;
    END
  END r0_rd_out[50]
  PIN r0_rd_out[51]
    DIRECTION OUTPUT ;
    USE SIGNAL ;
    SHAPE ABUTMENT ;
    PORT
      LAYER metal2 ;
      RECT 194.905 478.590 194.975 478.800 ;
    END
  END r0_rd_out[51]
  PIN r0_rd_out[52]
    DIRECTION OUTPUT ;
    USE SIGNAL ;
    SHAPE ABUTMENT ;
    PORT
      LAYER metal2 ;
      RECT 198.705 478.590 198.775 478.800 ;
    END
  END r0_rd_out[52]
  PIN r0_rd_out[53]
    DIRECTION OUTPUT ;
    USE SIGNAL ;
    SHAPE ABUTMENT ;
    PORT
      LAYER metal2 ;
      RECT 202.505 478.590 202.575 478.800 ;
    END
  END r0_rd_out[53]
  PIN r0_rd_out[54]
    DIRECTION OUTPUT ;
    USE SIGNAL ;
    SHAPE ABUTMENT ;
    PORT
      LAYER metal2 ;
      RECT 206.305 478.590 206.375 478.800 ;
    END
  END r0_rd_out[54]
  PIN r0_rd_out[55]
    DIRECTION OUTPUT ;
    USE SIGNAL ;
    SHAPE ABUTMENT ;
    PORT
      LAYER metal2 ;
      RECT 210.105 478.590 210.175 478.800 ;
    END
  END r0_rd_out[55]
  PIN r0_rd_out[56]
    DIRECTION OUTPUT ;
    USE SIGNAL ;
    SHAPE ABUTMENT ;
    PORT
      LAYER metal2 ;
      RECT 213.905 478.590 213.975 478.800 ;
    END
  END r0_rd_out[56]
  PIN r0_rd_out[57]
    DIRECTION OUTPUT ;
    USE SIGNAL ;
    SHAPE ABUTMENT ;
    PORT
      LAYER metal2 ;
      RECT 217.705 478.590 217.775 478.800 ;
    END
  END r0_rd_out[57]
  PIN r0_rd_out[58]
    DIRECTION OUTPUT ;
    USE SIGNAL ;
    SHAPE ABUTMENT ;
    PORT
      LAYER metal2 ;
      RECT 221.505 478.590 221.575 478.800 ;
    END
  END r0_rd_out[58]
  PIN r0_rd_out[59]
    DIRECTION OUTPUT ;
    USE SIGNAL ;
    SHAPE ABUTMENT ;
    PORT
      LAYER metal2 ;
      RECT 225.305 478.590 225.375 478.800 ;
    END
  END r0_rd_out[59]
  PIN r0_rd_out[60]
    DIRECTION OUTPUT ;
    USE SIGNAL ;
    SHAPE ABUTMENT ;
    PORT
      LAYER metal2 ;
      RECT 229.105 478.590 229.175 478.800 ;
    END
  END r0_rd_out[60]
  PIN r0_rd_out[61]
    DIRECTION OUTPUT ;
    USE SIGNAL ;
    SHAPE ABUTMENT ;
    PORT
      LAYER metal2 ;
      RECT 232.905 478.590 232.975 478.800 ;
    END
  END r0_rd_out[61]
  PIN r0_rd_out[62]
    DIRECTION OUTPUT ;
    USE SIGNAL ;
    SHAPE ABUTMENT ;
    PORT
      LAYER metal2 ;
      RECT 236.705 478.590 236.775 478.800 ;
    END
  END r0_rd_out[62]
  PIN r0_rd_out[63]
    DIRECTION OUTPUT ;
    USE SIGNAL ;
    SHAPE ABUTMENT ;
    PORT
      LAYER metal2 ;
      RECT 240.505 478.590 240.575 478.800 ;
    END
  END r0_rd_out[63]
  PIN rw0_addr_in[0]
    DIRECTION INPUT ;
    USE SIGNAL ;
    SHAPE ABUTMENT ;
    PORT
      LAYER metal3 ;
      RECT 0.000 294.245 0.210 294.315 ;
    END
  END rw0_addr_in[0]
  PIN rw0_addr_in[1]
    DIRECTION INPUT ;
    USE SIGNAL ;
    SHAPE ABUTMENT ;
    PORT
      LAYER metal3 ;
      RECT 0.000 312.585 0.210 312.655 ;
    END
  END rw0_addr_in[1]
  PIN rw0_addr_in[2]
    DIRECTION INPUT ;
    USE SIGNAL ;
    SHAPE ABUTMENT ;
    PORT
      LAYER metal3 ;
      RECT 0.000 330.925 0.210 330.995 ;
    END
  END rw0_addr_in[2]
  PIN rw0_addr_in[3]
    DIRECTION INPUT ;
    USE SIGNAL ;
    SHAPE ABUTMENT ;
    PORT
      LAYER metal3 ;
      RECT 0.000 349.265 0.210 349.335 ;
    END
  END rw0_addr_in[3]
  PIN rw0_addr_in[4]
    DIRECTION INPUT ;
    USE SIGNAL ;
    SHAPE ABUTMENT ;
    PORT
      LAYER metal3 ;
      RECT 0.000 367.605 0.210 367.675 ;
    END
  END rw0_addr_in[4]
  PIN rw0_addr_in[5]
    DIRECTION INPUT ;
    USE SIGNAL ;
    SHAPE ABUTMENT ;
    PORT
      LAYER metal3 ;
      RECT 272.250 294.245 272.460 294.315 ;
    END
  END rw0_addr_in[5]
  PIN rw0_addr_in[6]
    DIRECTION INPUT ;
    USE SIGNAL ;
    SHAPE ABUTMENT ;
    PORT
      LAYER metal3 ;
      RECT 272.250 312.585 272.460 312.655 ;
    END
  END rw0_addr_in[6]
  PIN rw0_addr_in[7]
    DIRECTION INPUT ;
    USE SIGNAL ;
    SHAPE ABUTMENT ;
    PORT
      LAYER metal3 ;
      RECT 272.250 330.925 272.460 330.995 ;
    END
  END rw0_addr_in[7]
  PIN rw0_addr_in[8]
    DIRECTION INPUT ;
    USE SIGNAL ;
    SHAPE ABUTMENT ;
    PORT
      LAYER metal3 ;
      RECT 272.250 349.265 272.460 349.335 ;
    END
  END rw0_addr_in[8]
  PIN rw0_addr_in[9]
    DIRECTION INPUT ;
    USE SIGNAL ;
    SHAPE ABUTMENT ;
    PORT
      LAYER metal3 ;
      RECT 272.250 367.605 272.460 367.675 ;
    END
  END rw0_addr_in[9]
  PIN r0_addr_in[0]
    DIRECTION INPUT ;
    USE SIGNAL ;
    SHAPE ABUTMENT ;
    PORT
      LAYER metal3 ;
      RECT 0.000 385.945 0.210 386.015 ;
    END
  END r0_addr_in[0]
  PIN r0_addr_in[1]
    DIRECTION INPUT ;
    USE SIGNAL ;
    SHAPE ABUTMENT ;
    PORT
      LAYER metal3 ;
      RECT 0.000 404.285 0.210 404.355 ;
    END
  END r0_addr_in[1]
  PIN r0_addr_in[2]
    DIRECTION INPUT ;
    USE SIGNAL ;
    SHAPE ABUTMENT ;
    PORT
      LAYER metal3 ;
      RECT 0.000 422.625 0.210 422.695 ;
    END
  END r0_addr_in[2]
  PIN r0_addr_in[3]
    DIRECTION INPUT ;
    USE SIGNAL ;
    SHAPE ABUTMENT ;
    PORT
      LAYER metal3 ;
      RECT 0.000 440.965 0.210 441.035 ;
    END
  END r0_addr_in[3]
  PIN r0_addr_in[4]
    DIRECTION INPUT ;
    USE SIGNAL ;
    SHAPE ABUTMENT ;
    PORT
      LAYER metal3 ;
      RECT 0.000 459.305 0.210 459.375 ;
    END
  END r0_addr_in[4]
  PIN r0_addr_in[5]
    DIRECTION INPUT ;
    USE SIGNAL ;
    SHAPE ABUTMENT ;
    PORT
      LAYER metal3 ;
      RECT 272.250 385.945 272.460 386.015 ;
    END
  END r0_addr_in[5]
  PIN r0_addr_in[6]
    DIRECTION INPUT ;
    USE SIGNAL ;
    SHAPE ABUTMENT ;
    PORT
      LAYER metal3 ;
      RECT 272.250 404.285 272.460 404.355 ;
    END
  END r0_addr_in[6]
  PIN r0_addr_in[7]
    DIRECTION INPUT ;
    USE SIGNAL ;
    SHAPE ABUTMENT ;
    PORT
      LAYER metal3 ;
      RECT 272.250 422.625 272.460 422.695 ;
    END
  END r0_addr_in[7]
  PIN r0_addr_in[8]
    DIRECTION INPUT ;
    USE SIGNAL ;
    SHAPE ABUTMENT ;
    PORT
      LAYER metal3 ;
      RECT 272.250 440.965 272.460 441.035 ;
    END
  END r0_addr_in[8]
  PIN r0_addr_in[9]
    DIRECTION INPUT ;
    USE SIGNAL ;
    SHAPE ABUTMENT ;
    PORT
      LAYER metal3 ;
      RECT 272.250 459.305 272.460 459.375 ;
    END
  END r0_addr_in[9]
  PIN rw0_we_in
    DIRECTION INPUT ;
    USE SIGNAL ;
    SHAPE ABUTMENT ;
    PORT
      LAYER metal2 ;
      RECT 244.305 478.590 244.375 478.800 ;
    END
  END rw0_we_in
  PIN rw0_ce_in
    DIRECTION INPUT ;
    USE SIGNAL ;
    SHAPE ABUTMENT ;
    PORT
      LAYER metal2 ;
      RECT 248.105 478.590 248.175 478.800 ;
    END
  END rw0_ce_in
  PIN rw0_clk
    DIRECTION INPUT ;
    USE SIGNAL ;
    SHAPE ABUTMENT ;
    PORT
      LAYER metal2 ;
      RECT 251.905 478.590 251.975 478.800 ;
    END
  END rw0_clk
  PIN r0_ce_in
    DIRECTION INPUT ;
    USE SIGNAL ;
    SHAPE ABUTMENT ;
    PORT
      LAYER metal2 ;
      RECT 255.705 478.590 255.775 478.800 ;
    END
  END r0_ce_in
  PIN r0_clk
    DIRECTION INPUT ;
    USE SIGNAL ;
    SHAPE ABUTMENT ;
    PORT
      LAYER metal2 ;
      RECT 259.505 478.590 259.575 478.800 ;
    END
  END r0_clk
  PIN VSS
    DIRECTION INOUT ;
    USE GROUND ;
    PORT
      LAYER metal4 ;
      RECT 1.000 0.840 1.280 477.960 ;
      RECT 3.240 0.840 3.520 477.960 ;
      RECT 5.480 0.840 5.760 477.960 ;
      RECT 7.720 0.840 8.000 477.960 ;
      RECT 9.960 0.840 10.240 477.960 ;
      RECT 12.200 0.840 12.480 477.960 ;
      RECT 14.440 0.840 14.720 477.960 ;
      RECT 16.680 0.840 16.960 477.960 ;
      RECT 18.920 0.840 19.200 477.960 ;
      RECT 21.160 0.840 21.440 477.960 ;
      RECT 23.400 0.840 23.680 477.960 ;
      RECT 25.640 0.840 25.920 477.960 ;
      RECT 27.880 0.840 28.160 477.960 ;
      RECT 30.120 0.840 30.400 477.960 ;
      RECT 32.360 0.840 32.640 477.960 ;
      RECT 34.600 0.840 34.880 477.960 ;
      RECT 36.840 0.840 37.120 477.960 ;
      RECT 39.080 0.840 39.360 477.960 ;
      RECT 41.320 0.840 41.600 477.960 ;
      RECT 43.560 0.840 43.840 477.960 ;
      RECT 45.800 0.840 46.080 477.960 ;
      RECT 48.040 0.840 48.320 477.960 ;
      RECT 50.280 0.840 50.560 477.960 ;
      RECT 52.520 0.840 52.800 477.960 ;
      RECT 54.760 0.840 55.040 477.960 ;
      RECT 57.000 0.840 57.280 477.960 ;
      RECT 59.240 0.840 59.520 477.960 ;
      RECT 61.480 0.840 61.760 477.960 ;
      RECT 63.720 0.840 64.000 477.960 ;
      RECT 65.960 0.840 66.240 477.960 ;
      RECT 68.200 0.840 68.480 477.960 ;
      RECT 70.440 0.840 70.720 477.960 ;
      RECT 72.680 0.840 72.960 477.960 ;
      RECT 74.920 0.840 75.200 477.960 ;
      RECT 77.160 0.840 77.440 477.960 ;
      RECT 79.400 0.840 79.680 477.960 ;
      RECT 81.640 0.840 81.920 477.960 ;
      RECT 83.880 0.840 84.160 477.960 ;
      RECT 86.120 0.840 86.400 477.960 ;
      RECT 88.360 0.840 88.640 477.960 ;
      RECT 90.600 0.840 90.880 477.960 ;
      RECT 92.840 0.840 93.120 477.960 ;
      RECT 95.080 0.840 95.360 477.960 ;
      RECT 97.320 0.840 97.600 477.960 ;
      RECT 99.560 0.840 99.840 477.960 ;
      RECT 101.800 0.840 102.080 477.960 ;
      RECT 104.040 0.840 104.320 477.960 ;
      RECT 106.280 0.840 106.560 477.960 ;
      RECT 108.520 0.840 108.800 477.960 ;
      RECT 110.760 0.840 111.040 477.960 ;
      RECT 113.000 0.840 113.280 477.960 ;
      RECT 115.240 0.840 115.520 477.960 ;
      RECT 117.480 0.840 117.760 477.960 ;
      RECT 119.720 0.840 120.000 477.960 ;
      RECT 121.960 0.840 122.240 477.960 ;
      RECT 124.200 0.840 124.480 477.960 ;
      RECT 126.440 0.840 126.720 477.960 ;
      RECT 128.680 0.840 128.960 477.960 ;
      RECT 130.920 0.840 131.200 477.960 ;
      RECT 133.160 0.840 133.440 477.960 ;
      RECT 135.400 0.840 135.680 477.960 ;
      RECT 137.640 0.840 137.920 477.960 ;
      RECT 139.880 0.840 140.160 477.960 ;
      RECT 142.120 0.840 142.400 477.960 ;
      RECT 144.360 0.840 144.640 477.960 ;
      RECT 146.600 0.840 146.880 477.960 ;
      RECT 148.840 0.840 149.120 477.960 ;
      RECT 151.080 0.840 151.360 477.960 ;
      RECT 153.320 0.840 153.600 477.960 ;
      RECT 155.560 0.840 155.840 477.960 ;
      RECT 157.800 0.840 158.080 477.960 ;
      RECT 160.040 0.840 160.320 477.960 ;
      RECT 162.280 0.840 162.560 477.960 ;
      RECT 164.520 0.840 164.800 477.960 ;
      RECT 166.760 0.840 167.040 477.960 ;
      RECT 169.000 0.840 169.280 477.960 ;
      RECT 171.240 0.840 171.520 477.960 ;
      RECT 173.480 0.840 173.760 477.960 ;
      RECT 175.720 0.840 176.000 477.960 ;
      RECT 177.960 0.840 178.240 477.960 ;
      RECT 180.200 0.840 180.480 477.960 ;
      RECT 182.440 0.840 182.720 477.960 ;
      RECT 184.680 0.840 184.960 477.960 ;
      RECT 186.920 0.840 187.200 477.960 ;
      RECT 189.160 0.840 189.440 477.960 ;
      RECT 191.400 0.840 191.680 477.960 ;
      RECT 193.640 0.840 193.920 477.960 ;
      RECT 195.880 0.840 196.160 477.960 ;
      RECT 198.120 0.840 198.400 477.960 ;
      RECT 200.360 0.840 200.640 477.960 ;
      RECT 202.600 0.840 202.880 477.960 ;
      RECT 204.840 0.840 205.120 477.960 ;
      RECT 207.080 0.840 207.360 477.960 ;
      RECT 209.320 0.840 209.600 477.960 ;
      RECT 211.560 0.840 211.840 477.960 ;
      RECT 213.800 0.840 214.080 477.960 ;
      RECT 216.040 0.840 216.320 477.960 ;
      RECT 218.280 0.840 218.560 477.960 ;
      RECT 220.520 0.840 220.800 477.960 ;
      RECT 222.760 0.840 223.040 477.960 ;
      RECT 225.000 0.840 225.280 477.960 ;
      RECT 227.240 0.840 227.520 477.960 ;
      RECT 229.480 0.840 229.760 477.960 ;
      RECT 231.720 0.840 232.000 477.960 ;
      RECT 233.960 0.840 234.240 477.960 ;
      RECT 236.200 0.840 236.480 477.960 ;
      RECT 238.440 0.840 238.720 477.960 ;
      RECT 240.680 0.840 240.960 477.960 ;
      RECT 242.920 0.840 243.200 477.960 ;
      RECT 245.160 0.840 245.440 477.960 ;
      RECT 247.400 0.840 247.680 477.960 ;
      RECT 249.640 0.840 249.920 477.960 ;
      RECT 251.880 0.840 252.160 477.960 ;
      RECT 254.120 0.840 254.400 477.960 ;
      RECT 256.360 0.840 256.640 477.960 ;
      RECT 258.600 0.840 258.880 477.960 ;
      RECT 260.840 0.840 261.120 477.960 ;
      RECT 263.080 0.840 263.360 477.960 ;
      RECT 265.320 0.840 265.600 477.960 ;
      RECT 267.560 0.840 267.840 477.960 ;
      RECT 269.800 0.840 270.080 477.960 ;
      RECT 272.040 0.840 272.320 477.960 ;
    END
  END VSS
  PIN VDD
    DIRECTION INOUT ;
    USE POWER ;
    PORT
      LAYER metal4 ;
      RECT 2.120 0.840 2.400 477.960 ;
      RECT 4.360 0.840 4.640 477.960 ;
      RECT 6.600 0.840 6.880 477.960 ;
      RECT 8.840 0.840 9.120 477.960 ;
      RECT 11.080 0.840 11.360 477.960 ;
      RECT 13.320 0.840 13.600 477.960 ;
      RECT 15.560 0.840 15.840 477.960 ;
      RECT 17.800 0.840 18.080 477.960 ;
      RECT 20.040 0.840 20.320 477.960 ;
      RECT 22.280 0.840 22.560 477.960 ;
      RECT 24.520 0.840 24.800 477.960 ;
      RECT 26.760 0.840 27.040 477.960 ;
      RECT 29.000 0.840 29.280 477.960 ;
      RECT 31.240 0.840 31.520 477.960 ;
      RECT 33.480 0.840 33.760 477.960 ;
      RECT 35.720 0.840 36.000 477.960 ;
      RECT 37.960 0.840 38.240 477.960 ;
      RECT 40.200 0.840 40.480 477.960 ;
      RECT 42.440 0.840 42.720 477.960 ;
      RECT 44.680 0.840 44.960 477.960 ;
      RECT 46.920 0.840 47.200 477.960 ;
      RECT 49.160 0.840 49.440 477.960 ;
      RECT 51.400 0.840 51.680 477.960 ;
      RECT 53.640 0.840 53.920 477.960 ;
      RECT 55.880 0.840 56.160 477.960 ;
      RECT 58.120 0.840 58.400 477.960 ;
      RECT 60.360 0.840 60.640 477.960 ;
      RECT 62.600 0.840 62.880 477.960 ;
      RECT 64.840 0.840 65.120 477.960 ;
      RECT 67.080 0.840 67.360 477.960 ;
      RECT 69.320 0.840 69.600 477.960 ;
      RECT 71.560 0.840 71.840 477.960 ;
      RECT 73.800 0.840 74.080 477.960 ;
      RECT 76.040 0.840 76.320 477.960 ;
      RECT 78.280 0.840 78.560 477.960 ;
      RECT 80.520 0.840 80.800 477.960 ;
      RECT 82.760 0.840 83.040 477.960 ;
      RECT 85.000 0.840 85.280 477.960 ;
      RECT 87.240 0.840 87.520 477.960 ;
      RECT 89.480 0.840 89.760 477.960 ;
      RECT 91.720 0.840 92.000 477.960 ;
      RECT 93.960 0.840 94.240 477.960 ;
      RECT 96.200 0.840 96.480 477.960 ;
      RECT 98.440 0.840 98.720 477.960 ;
      RECT 100.680 0.840 100.960 477.960 ;
      RECT 102.920 0.840 103.200 477.960 ;
      RECT 105.160 0.840 105.440 477.960 ;
      RECT 107.400 0.840 107.680 477.960 ;
      RECT 109.640 0.840 109.920 477.960 ;
      RECT 111.880 0.840 112.160 477.960 ;
      RECT 114.120 0.840 114.400 477.960 ;
      RECT 116.360 0.840 116.640 477.960 ;
      RECT 118.600 0.840 118.880 477.960 ;
      RECT 120.840 0.840 121.120 477.960 ;
      RECT 123.080 0.840 123.360 477.960 ;
      RECT 125.320 0.840 125.600 477.960 ;
      RECT 127.560 0.840 127.840 477.960 ;
      RECT 129.800 0.840 130.080 477.960 ;
      RECT 132.040 0.840 132.320 477.960 ;
      RECT 134.280 0.840 134.560 477.960 ;
      RECT 136.520 0.840 136.800 477.960 ;
      RECT 138.760 0.840 139.040 477.960 ;
      RECT 141.000 0.840 141.280 477.960 ;
      RECT 143.240 0.840 143.520 477.960 ;
      RECT 145.480 0.840 145.760 477.960 ;
      RECT 147.720 0.840 148.000 477.960 ;
      RECT 149.960 0.840 150.240 477.960 ;
      RECT 152.200 0.840 152.480 477.960 ;
      RECT 154.440 0.840 154.720 477.960 ;
      RECT 156.680 0.840 156.960 477.960 ;
      RECT 158.920 0.840 159.200 477.960 ;
      RECT 161.160 0.840 161.440 477.960 ;
      RECT 163.400 0.840 163.680 477.960 ;
      RECT 165.640 0.840 165.920 477.960 ;
      RECT 167.880 0.840 168.160 477.960 ;
      RECT 170.120 0.840 170.400 477.960 ;
      RECT 172.360 0.840 172.640 477.960 ;
      RECT 174.600 0.840 174.880 477.960 ;
      RECT 176.840 0.840 177.120 477.960 ;
      RECT 179.080 0.840 179.360 477.960 ;
      RECT 181.320 0.840 181.600 477.960 ;
      RECT 183.560 0.840 183.840 477.960 ;
      RECT 185.800 0.840 186.080 477.960 ;
      RECT 188.040 0.840 188.320 477.960 ;
      RECT 190.280 0.840 190.560 477.960 ;
      RECT 192.520 0.840 192.800 477.960 ;
      RECT 194.760 0.840 195.040 477.960 ;
      RECT 197.000 0.840 197.280 477.960 ;
      RECT 199.240 0.840 199.520 477.960 ;
      RECT 201.480 0.840 201.760 477.960 ;
      RECT 203.720 0.840 204.000 477.960 ;
      RECT 205.960 0.840 206.240 477.960 ;
      RECT 208.200 0.840 208.480 477.960 ;
      RECT 210.440 0.840 210.720 477.960 ;
      RECT 212.680 0.840 212.960 477.960 ;
      RECT 214.920 0.840 215.200 477.960 ;
      RECT 217.160 0.840 217.440 477.960 ;
      RECT 219.400 0.840 219.680 477.960 ;
      RECT 221.640 0.840 221.920 477.960 ;
      RECT 223.880 0.840 224.160 477.960 ;
      RECT 226.120 0.840 226.400 477.960 ;
      RECT 228.360 0.840 228.640 477.960 ;
      RECT 230.600 0.840 230.880 477.960 ;
      RECT 232.840 0.840 233.120 477.960 ;
      RECT 235.080 0.840 235.360 477.960 ;
      RECT 237.320 0.840 237.600 477.960 ;
      RECT 239.560 0.840 239.840 477.960 ;
      RECT 241.800 0.840 242.080 477.960 ;
      RECT 244.040 0.840 244.320 477.960 ;
      RECT 246.280 0.840 246.560 477.960 ;
      RECT 248.520 0.840 248.800 477.960 ;
      RECT 250.760 0.840 251.040 477.960 ;
      RECT 253.000 0.840 253.280 477.960 ;
      RECT 255.240 0.840 255.520 477.960 ;
      RECT 257.480 0.840 257.760 477.960 ;
      RECT 259.720 0.840 260.000 477.960 ;
      RECT 261.960 0.840 262.240 477.960 ;
      RECT 264.200 0.840 264.480 477.960 ;
      RECT 266.440 0.840 266.720 477.960 ;
      RECT 268.680 0.840 268.960 477.960 ;
      RECT 270.920 0.840 271.200 477.960 ;
    END
  END VDD
  OBS
    LAYER metal1 ;
    RECT 0 0 272.460 478.800 ;
    LAYER metal2 ;
    RECT 0 0 272.460 478.800 ;
    LAYER metal3 ;
    RECT 0 0 272.460 478.800 ;
    LAYER metal4 ;
    RECT 0 0 272.460 478.800 ;
    LAYER OVERLAP ;
    RECT 0 0 272.460 478.800 ;
  END
END fakeram_1rw1r_64w1024d_sram

END LIBRARY
